VERSION 5.8 ;
BUSBITCHARS "[]" ;
DIVIDERCHAR "/" ;

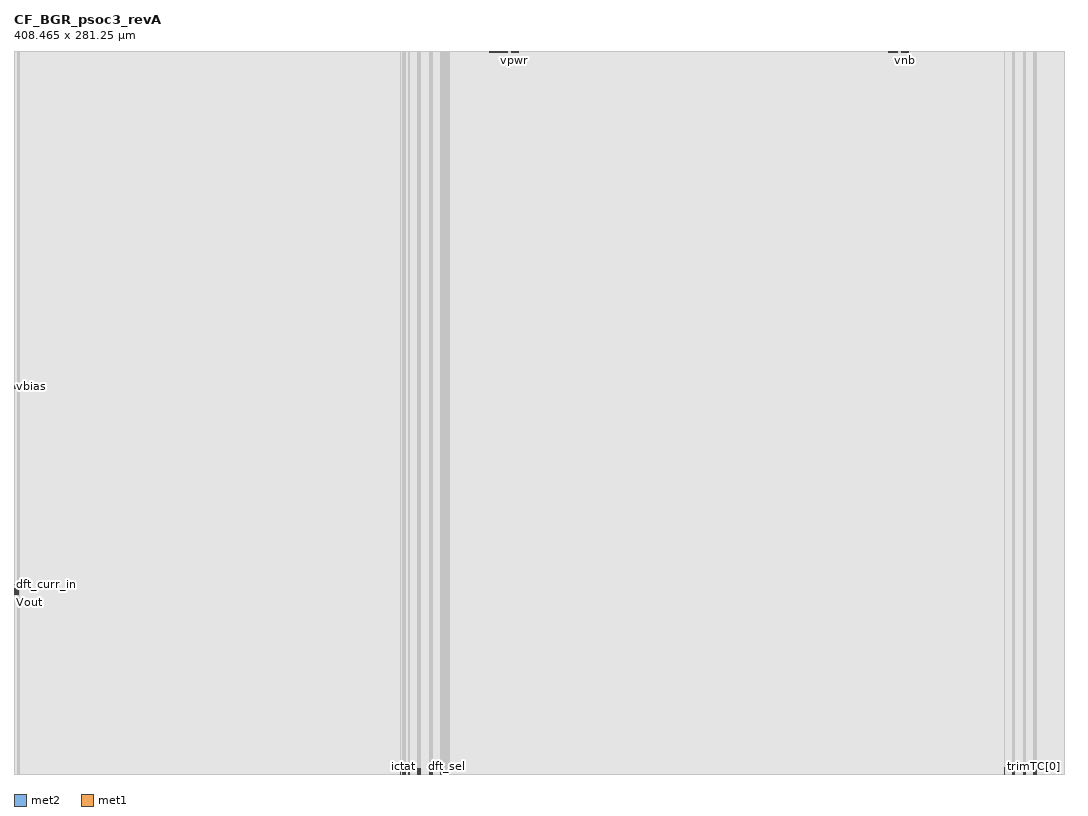
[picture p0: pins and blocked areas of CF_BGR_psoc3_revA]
MACRO CF_BGR_psoc3_revA
  ORIGIN 0 0 ;
  SIZE 408.465 BY 281.25 ;
  PIN CurrAbsTrim[5]
    DIRECTION INOUT ;
    USE SIGNAL ;
    PORT
      LAYER met2 ;
        RECT 166.425 0 166.565 2.085 ;
    END
  END CurrAbsTrim[5]
  PIN trimCurr[5]
    DIRECTION INPUT ;
    USE SIGNAL ;
    PORT
      LAYER met2 ;
        RECT 153.295 0 153.435 2.085 ;
    END
  END trimCurr[5]
  PIN trimCurr[4]
    DIRECTION INPUT ;
    USE SIGNAL ;
    PORT
      LAYER met2 ;
        RECT 157.055 0 157.195 2.085 ;
    END
  END trimCurr[4]
  PIN trimCurr[3]
    DIRECTION INPUT ;
    USE SIGNAL ;
    PORT
      LAYER met2 ;
        RECT 157.425 0 157.565 2.085 ;
    END
  END trimCurr[3]
  PIN trimCurr[2]
    DIRECTION INPUT ;
    USE SIGNAL ;
    PORT
      LAYER met2 ;
        RECT 157.795 0 157.935 2.085 ;
    END
  END trimCurr[2]
  PIN trimCurr[0]
    DIRECTION INPUT ;
    USE SIGNAL ;
    PORT
      LAYER met2 ;
        RECT 158.165 0 158.305 2.085 ;
    END
  END trimCurr[0]
  PIN trimCurr[1]
    DIRECTION INPUT ;
    USE SIGNAL ;
    PORT
      LAYER met2 ;
        RECT 161.555 0 161.695 2.085 ;
    END
  END trimCurr[1]
  PIN CurrAbsTrim[0]
    DIRECTION INPUT ;
    USE SIGNAL ;
    PORT
      LAYER met2 ;
        RECT 153.665 0 153.805 2.085 ;
    END
  END CurrAbsTrim[0]
  PIN CurrAbsTrim[1]
    DIRECTION INPUT ;
    USE SIGNAL ;
    PORT
      LAYER met2 ;
        RECT 161.925 0 162.065 2.085 ;
    END
  END CurrAbsTrim[1]
  PIN CurrAbsTrim[2]
    DIRECTION INPUT ;
    USE SIGNAL ;
    PORT
      LAYER met2 ;
        RECT 162.295 0 162.435 2.085 ;
    END
  END CurrAbsTrim[2]
  PIN CurrAbsTrim[3]
    DIRECTION INPUT ;
    USE SIGNAL ;
    PORT
      LAYER met2 ;
        RECT 162.665 0 162.805 2.085 ;
    END
  END CurrAbsTrim[3]
  PIN CurrAbsTrim[4]
    DIRECTION INOUT ;
    USE SIGNAL ;
    PORT
      LAYER met2 ;
        RECT 166.055 0 166.195 2.085 ;
    END
  END CurrAbsTrim[4]
  PIN mux2sel
    DIRECTION INPUT ;
    USE SIGNAL ;
    PORT
      LAYER met2 ;
        RECT 167.16 0 167.3 1.065 ;
    END
  END mux2sel
  PIN mux1sel[0]
    DIRECTION INPUT ;
    USE SIGNAL ;
    PORT
      LAYER met2 ;
        RECT 167.53 0 167.67 1.065 ;
    END
  END mux1sel[0]
  PIN mux1sel[1]
    DIRECTION INPUT ;
    USE SIGNAL ;
    PORT
      LAYER met2 ;
        RECT 167.9 0 168.04 1.065 ;
    END
  END mux1sel[1]
  PIN dft_sel
    DIRECTION INPUT ;
    USE SIGNAL ;
    PORT
      LAYER met2 ;
        RECT 168.27 0 168.41 1.065 ;
    END
  END dft_sel
  PIN pd_ibg
    DIRECTION INPUT ;
    USE SIGNAL ;
    PORT
      LAYER met2 ;
        RECT 168.65 0 168.79 1.065 ;
    END
  END pd_ibg
  PIN pd
    DIRECTION INPUT ;
    USE SIGNAL ;
    PORT
      LAYER met2 ;
        RECT 169.095 0 169.235 1.065 ;
    END
  END pd
  PIN trimTC[6]
    DIRECTION INPUT ;
    USE SIGNAL ;
    PORT
      LAYER met2 ;
        RECT 385.145 0 385.285 2.375 ;
    END
  END trimTC[6]
  PIN trimTC[5]
    DIRECTION INPUT ;
    USE SIGNAL ;
    PORT
      LAYER met2 ;
        RECT 388.535 0 388.675 2.375 ;
    END
  END trimTC[5]
  PIN trimTC[4]
    DIRECTION INPUT ;
    USE SIGNAL ;
    PORT
      LAYER met2 ;
        RECT 389.18 0 389.32 2.375 ;
    END
  END trimTC[4]
  PIN trimTC[3]
    DIRECTION INPUT ;
    USE SIGNAL ;
    PORT
      LAYER met2 ;
        RECT 392.57 0 392.71 2.375 ;
    END
  END trimTC[3]
  PIN trimTC[2]
    DIRECTION INPUT ;
    USE SIGNAL ;
    PORT
      LAYER met2 ;
        RECT 393.27 0 393.41 2.375 ;
    END
  END trimTC[2]
  PIN trimTC[0]
    DIRECTION INPUT ;
    USE SIGNAL ;
    PORT
      LAYER met2 ;
        RECT 396.66 0 396.8 2.375 ;
    END
  END trimTC[0]
  PIN trimTC[1]
    DIRECTION INPUT ;
    USE SIGNAL ;
    PORT
      LAYER met2 ;
        RECT 397.535 0 397.675 2.375 ;
    END
  END trimTC[1]
  PIN inl_ctrl[0]
    DIRECTION INPUT ;
    USE SIGNAL ;
    PORT
      LAYER met2 ;
        RECT 150.955 0 151.095 2.085 ;
    END
  END inl_ctrl[0]
  PIN inl_ctrl[1]
    DIRECTION INPUT ;
    USE SIGNAL ;
    PORT
      LAYER met2 ;
        RECT 150.355 0 150.495 2.085 ;
    END
  END inl_ctrl[1]
  PIN vbias_cascode
    DIRECTION OUTPUT ;
    USE SIGNAL ;
    PORT
      LAYER met2 ;
        RECT 0 150.03 2.075 150.17 ;
    END
  END vbias_cascode
  PIN vbias
    DIRECTION OUTPUT ;
    USE SIGNAL ;
    PORT
      LAYER met2 ;
        RECT 0 150.81 2.075 150.95 ;
    END
  END vbias
  PIN dft_curr_in
    DIRECTION INPUT ;
    USE SIGNAL ;
    PORT
      LAYER met2 ;
        RECT 0 73.7 1.495 73.84 ;
    END
  END dft_curr_in
  PIN Vout
    DIRECTION OUTPUT ;
    USE SIGNAL ;
    PORT
      LAYER met2 ;
        RECT 0 69.64 1.75 69.78 ;
    END
  END Vout
  PIN ibg_3uA
    DIRECTION OUTPUT ;
    USE SIGNAL ;
    PORT
      LAYER met2 ;
        RECT 0 70.14 1.75 70.28 ;
    END
  END ibg_3uA
  PIN ibg_2p375uA
    DIRECTION OUTPUT ;
    USE SIGNAL ;
    PORT
      LAYER met2 ;
        RECT 0 70.58 1.75 70.72 ;
    END
  END ibg_2p375uA
  PIN mux1out
    DIRECTION OUTPUT ;
    USE SIGNAL ;
    PORT
      LAYER met2 ;
        RECT 0 71.11 1.75 71.25 ;
    END
  END mux1out
  PIN mux2out
    DIRECTION OUTPUT ;
    USE SIGNAL ;
    PORT
      LAYER met2 ;
        RECT 0 71.905 1.75 72.045 ;
    END
  END mux2out
  PIN ictat
    DIRECTION OUTPUT ;
    USE SIGNAL ;
    PORT
      LAYER met2 ;
        RECT 151.615 0 151.755 1.065 ;
    END
  END ictat
  PIN iptat
    DIRECTION OUTPUT ;
    USE SIGNAL ;
    PORT
      LAYER met2 ;
        RECT 152.22 0 152.36 1.065 ;
    END
  END iptat
  PIN vpb
    DIRECTION INPUT ;
    USE SIGNAL ;
    PORT
      LAYER met1 ;
        RECT 184.955 280.85 192.08 281.25 ;
    END
  END vpb
  PIN vgnd
    DIRECTION INPUT ;
    USE SIGNAL ;
    PORT
      LAYER met1 ;
        RECT 340.21 280.85 343.78 281.25 ;
    END
  END vgnd
  PIN vnb
    DIRECTION INPUT ;
    USE SIGNAL ;
    PORT
      LAYER met1 ;
        RECT 345.205 280.85 347.975 281.25 ;
    END
  END vnb
  PIN vpwr
    DIRECTION INPUT ;
    USE SIGNAL ;
    PORT
      LAYER met1 ;
        RECT 193.455 280.85 196.235 281.25 ;
    END
  END vpwr
  OBS
    LAYER li1 ;
      RECT 0 0 408.465 281.25 ;
    LAYER met1 ;
      RECT 0 0 184.955 281.25 ;
      RECT 184.955 0 192.08 280.85 ;
      RECT 192.08 0 193.455 281.25 ;
      RECT 193.455 0 196.235 280.85 ;
      RECT 196.235 0 340.21 281.25 ;
      RECT 340.21 0 343.78 280.85 ;
      RECT 343.78 0 345.205 281.25 ;
      RECT 345.205 0 347.975 280.85 ;
      RECT 347.975 0 408.465 281.25 ;
    LAYER met2 ;
      RECT 0 0 1.495 69.64 ;
      RECT 0 69.78 1.495 70.14 ;
      RECT 0 70.28 1.495 70.58 ;
      RECT 0 70.72 1.495 71.11 ;
      RECT 0 71.25 1.495 71.905 ;
      RECT 0 72.045 1.495 73.7 ;
      RECT 0 73.84 1.495 150.03 ;
      RECT 0 150.17 1.495 150.81 ;
      RECT 0 150.95 1.495 281.25 ;
      RECT 1.495 0 1.75 69.64 ;
      RECT 1.495 69.78 1.75 70.14 ;
      RECT 1.495 70.28 1.75 70.58 ;
      RECT 1.495 70.72 1.75 71.11 ;
      RECT 1.495 71.25 1.75 71.905 ;
      RECT 1.495 72.045 1.75 150.03 ;
      RECT 1.495 150.17 1.75 150.81 ;
      RECT 1.495 150.95 1.75 281.25 ;
      RECT 1.75 0 2.075 150.03 ;
      RECT 1.75 150.17 2.075 150.81 ;
      RECT 1.75 150.95 2.075 281.25 ;
      RECT 2.075 0 150.355 281.25 ;
      RECT 150.355 2.085 150.495 281.25 ;
      RECT 150.495 0 150.955 281.25 ;
      RECT 150.955 2.085 151.095 281.25 ;
      RECT 151.095 0 151.615 281.25 ;
      RECT 151.615 1.065 151.755 281.25 ;
      RECT 151.755 0 152.22 281.25 ;
      RECT 152.22 1.065 152.36 281.25 ;
      RECT 152.36 0 153.295 281.25 ;
      RECT 153.295 2.085 153.435 281.25 ;
      RECT 153.435 0 153.665 281.25 ;
      RECT 153.665 2.085 153.805 281.25 ;
      RECT 153.805 0 157.055 281.25 ;
      RECT 157.055 2.085 157.195 281.25 ;
      RECT 157.195 0 157.425 281.25 ;
      RECT 157.425 2.085 157.565 281.25 ;
      RECT 157.565 0 157.795 281.25 ;
      RECT 157.795 2.085 157.935 281.25 ;
      RECT 157.935 0 158.165 281.25 ;
      RECT 158.165 2.085 158.305 281.25 ;
      RECT 158.305 0 161.555 281.25 ;
      RECT 161.555 2.085 161.695 281.25 ;
      RECT 161.695 0 161.925 281.25 ;
      RECT 161.925 2.085 162.065 281.25 ;
      RECT 162.065 0 162.295 281.25 ;
      RECT 162.295 2.085 162.435 281.25 ;
      RECT 162.435 0 162.665 281.25 ;
      RECT 162.665 2.085 162.805 281.25 ;
      RECT 162.805 0 166.055 281.25 ;
      RECT 166.055 2.085 166.195 281.25 ;
      RECT 166.195 0 166.425 281.25 ;
      RECT 166.425 2.085 166.565 281.25 ;
      RECT 166.565 0 167.16 281.25 ;
      RECT 167.16 1.065 167.3 281.25 ;
      RECT 167.3 0 167.53 281.25 ;
      RECT 167.53 1.065 167.67 281.25 ;
      RECT 167.67 0 167.9 281.25 ;
      RECT 167.9 1.065 168.04 281.25 ;
      RECT 168.04 0 168.27 281.25 ;
      RECT 168.27 1.065 168.41 281.25 ;
      RECT 168.41 0 168.65 281.25 ;
      RECT 168.65 1.065 168.79 281.25 ;
      RECT 168.79 0 169.095 281.25 ;
      RECT 169.095 1.065 169.235 281.25 ;
      RECT 169.235 0 385.145 281.25 ;
      RECT 385.145 2.375 385.285 281.25 ;
      RECT 385.285 0 388.535 281.25 ;
      RECT 388.535 2.375 388.675 281.25 ;
      RECT 388.675 0 389.18 281.25 ;
      RECT 389.18 2.375 389.32 281.25 ;
      RECT 389.32 0 392.57 281.25 ;
      RECT 392.57 2.375 392.71 281.25 ;
      RECT 392.71 0 393.27 281.25 ;
      RECT 393.27 2.375 393.41 281.25 ;
      RECT 393.41 0 396.66 281.25 ;
      RECT 396.66 2.375 396.8 281.25 ;
      RECT 396.8 0 397.535 281.25 ;
      RECT 397.535 2.375 397.675 281.25 ;
      RECT 397.675 0 408.465 281.25 ;
  END
END CF_BGR_psoc3_revA

END LIBRARY
